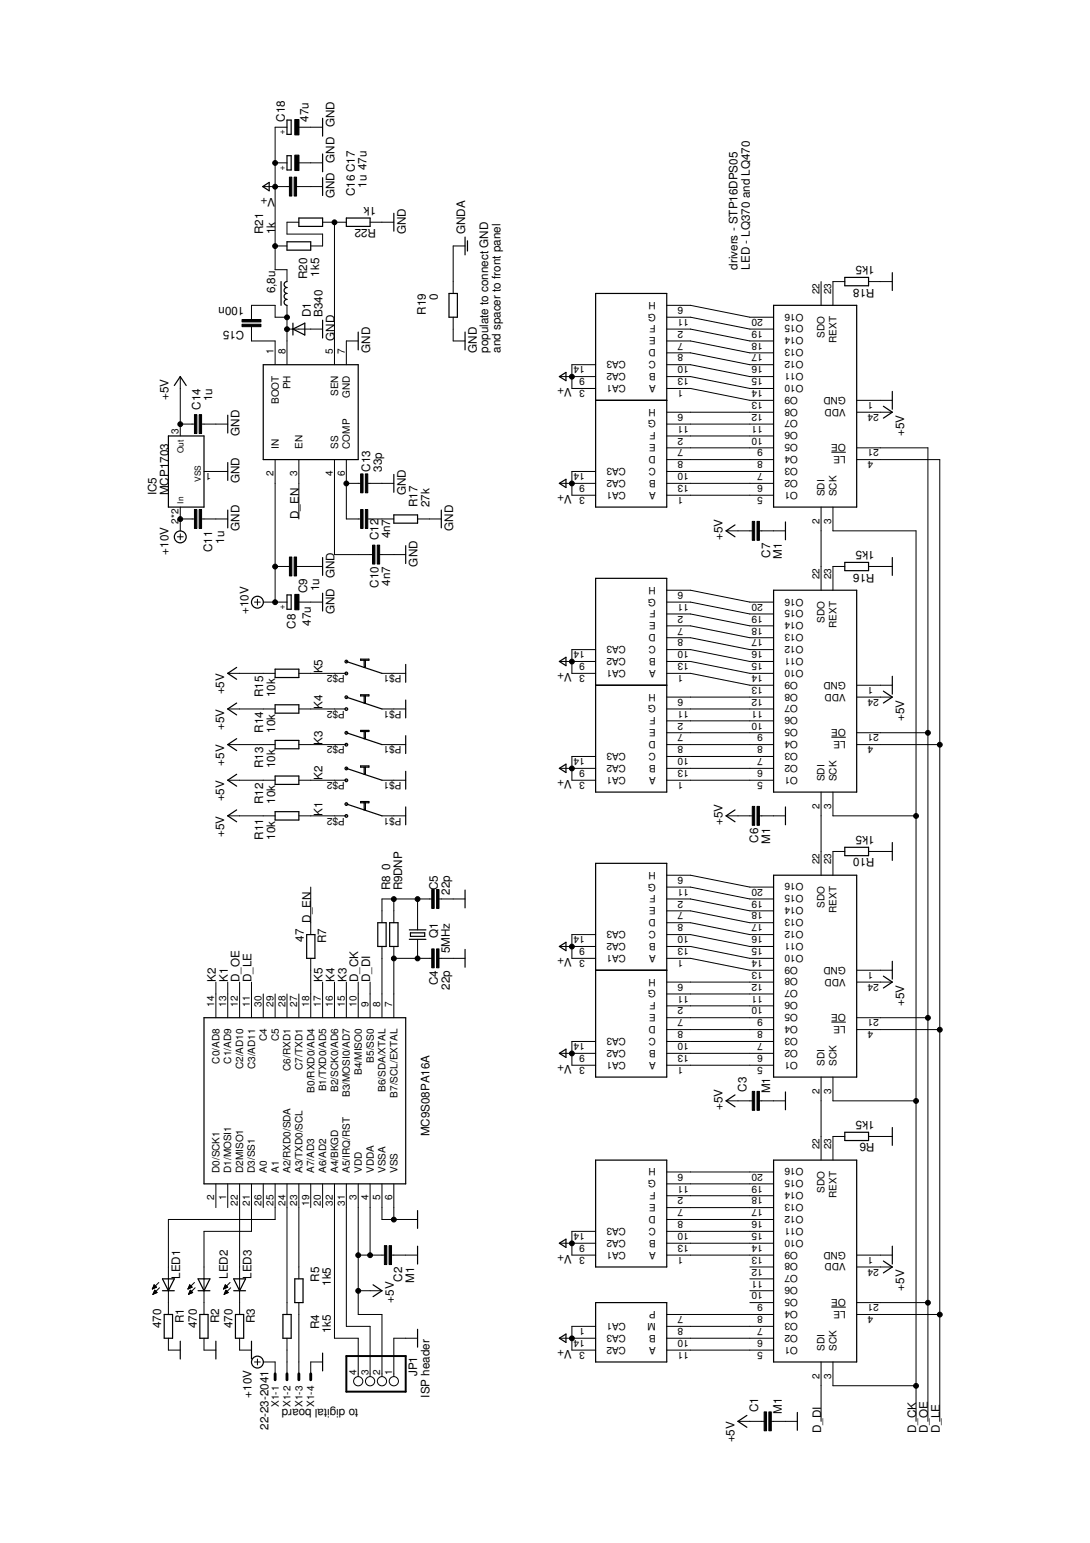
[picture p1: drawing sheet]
<svg xmlns="http://www.w3.org/2000/svg" width="210mm" height="297mm" viewBox="0 0 210 297" stroke-linecap="round" stroke-linejoin="round" font-family="sans-serif">
<defs><g id="words">
<g font-size="2.2">
<text x="54.8" y="23.5" transform="rotate(-90 54.8 23.5)">C18</text>
<text x="59.4" y="23.5" transform="rotate(-90 59.4 23.5)">47u</text>
<text x="64.4" y="24.5" transform="rotate(-90 64.4 24.5)">GND</text>
<text x="64.4" y="31.3" transform="rotate(-90 64.4 31.3)">GND</text>
<text x="53" y="38.2" transform="rotate(-180 53 38.2)">V+</text>
<text x="64.4" y="38.2" transform="rotate(-90 64.4 38.2)">GND</text>
<text x="68.3" y="37.7" transform="rotate(-90 68.3 37.7)">C16 C17</text>
<text x="70.6" y="36.1" transform="rotate(-90 70.6 36.1)">1u 47u</text>
<text x="72.4" y="39.8" transform="rotate(-180 72.4 39.8)">1k</text>
<text x="50.7" y="45.1" transform="rotate(-90 50.7 45.1)">R21</text>
<text x="53" y="45.1" transform="rotate(-90 53 45.1)">1k</text>
<text x="72.4" y="44.1" transform="rotate(-180 72.4 44.1)">R22</text>
<text x="78.1" y="45.1" transform="rotate(-90 78.1 45.1)">GND</text>
<text x="89.6" y="45.1" transform="rotate(-90 89.6 45.1)">GNDA</text>
<text x="59.2" y="53.7" transform="rotate(-90 59.2 53.7)">R20</text>
<text x="61.5" y="53.3" transform="rotate(-90 61.5 53.3)">1k5</text>
<text x="142" y="51.9" transform="rotate(-90 142 51.9)">drivers - STP16DPS05</text>
<text x="144.4" y="51.9" transform="rotate(-90 144.4 51.9)">LED - LQ370 and LQ470</text>
<text x="168.4" y="51.2" transform="rotate(-180 168.4 51.2)">1k5</text>
<text x="47" y="59.1" transform="rotate(-180 47 59.1)">100n</text>
<text x="53" y="56.5" transform="rotate(-90 53 56.5)">6,8u</text>
<text x="84.3" y="57.7" transform="rotate(-90 84.3 57.7)">0</text>
<text x="168.4" y="55.6" transform="rotate(-180 168.4 55.6)">R18</text>
<text x="47" y="63.7" transform="rotate(-180 47 63.7)">C15</text>
<text x="59.8" y="61.1" transform="rotate(-90 59.8 61.1)">D1</text>
<text x="62.1" y="61.1" transform="rotate(-90 62.1 61.1)">B340</text>
<text x="64.4" y="65.6" transform="rotate(-90 64.4 65.6)">GND</text>
<text x="82" y="60.6" transform="rotate(-90 82 60.6)">R19</text>
<text x="71.3" y="67.9" transform="rotate(-90 71.3 67.9)">GND</text>
<text x="91.8" y="67.9" transform="rotate(-90 91.8 67.9)">GND</text>
<text x="94" y="67.9" transform="rotate(-90 94 67.9)">populate to connect GND</text>
<text x="96.4" y="67.9" transform="rotate(-90 96.4 67.9)">and spacer to front panel</text>
<text x="32.4" y="77.1" transform="rotate(-90 32.4 77.1)">+5V</text>
<text x="40.9" y="77.3" transform="rotate(-90 40.9 77.3)">1u</text>
<text x="110.1" y="74.8" transform="rotate(-180 110.1 74.8)">V+</text>
<text x="38.6" y="78.9" transform="rotate(-90 38.6 78.9)">C14</text>
<text x="46.1" y="83.9" transform="rotate(-90 46.1 83.9)">GND</text>
<text x="174.1" y="83.9" transform="rotate(-90 174.1 83.9)">+5V</text>
<text x="30.1" y="95.3" transform="rotate(-90 30.1 95.3)">IC5</text>
<text x="32.4" y="95.3" transform="rotate(-90 32.4 95.3)">MCP1703</text>
<text x="46.1" y="93.1" transform="rotate(-90 46.1 93.1)">GND</text>
<text x="71.3" y="90.8" transform="rotate(-90 71.3 90.8)">C13</text>
<text x="73.6" y="90.8" transform="rotate(-90 73.6 90.8)">33p</text>
<text x="78.1" y="95.3" transform="rotate(-90 78.1 95.3)">GND</text>
<text x="110.1" y="95.3" transform="rotate(-180 110.1 95.3)">V+</text>
<text x="57.6" y="99.9" transform="rotate(-90 57.6 99.9)">D_EN</text>
<text x="80.4" y="97.6" transform="rotate(-90 80.4 97.6)">R17</text>
<text x="82.7" y="97.6" transform="rotate(-90 82.7 97.6)">27k</text>
<text x="32.4" y="106.8" transform="rotate(-90 32.4 106.8)">+10V</text>
<text x="40.9" y="106.3" transform="rotate(-90 40.9 106.3)">C11</text>
<text x="43.2" y="104.7" transform="rotate(-90 43.2 104.7)">1u</text>
<text x="46.1" y="102.2" transform="rotate(-90 46.1 102.2)">GND</text>
<text x="72.9" y="104" transform="rotate(-90 72.9 104)">C12</text>
<text x="75.2" y="103.7" transform="rotate(-90 75.2 103.7)">4n7</text>
<text x="87.3" y="102.2" transform="rotate(-90 87.3 102.2)">GND</text>
<text x="139.2" y="104" transform="rotate(-90 139.2 104)">+5V</text>
<text x="148.3" y="107.3" transform="rotate(-90 148.3 107.3)">C7</text>
<text x="150.6" y="107.6" transform="rotate(-90 150.6 107.6)">M1</text>
<text x="168.4" y="106.1" transform="rotate(-180 168.4 106.1)">1k5</text>
<text x="61.5" y="113.8" transform="rotate(-90 61.5 113.8)">1u</text>
<text x="64.4" y="111.3" transform="rotate(-90 64.4 111.3)">GND</text>
<text x="72.9" y="113.2" transform="rotate(-90 72.9 113.2)">C10</text>
<text x="75.2" y="112.8" transform="rotate(-90 75.2 112.8)">4n7</text>
<text x="80.4" y="109.1" transform="rotate(-90 80.4 109.1)">GND</text>
<text x="168.4" y="110.4" transform="rotate(-180 168.4 110.4)">R16</text>
<text x="47.8" y="118.2" transform="rotate(-90 47.8 118.2)">+10V</text>
<text x="59.2" y="114.2" transform="rotate(-90 59.2 114.2)">C9</text>
<text x="64.4" y="118.2" transform="rotate(-90 64.4 118.2)">GND</text>
<text x="56.9" y="121.1" transform="rotate(-90 56.9 121.1)">C8</text>
<text x="59.8" y="120.5" transform="rotate(-90 59.8 120.5)">47u</text>
<text x="62.1" y="129.6" transform="rotate(-90 62.1 129.6)">K5</text>
<text x="110.1" y="129.6" transform="rotate(-180 110.1 129.6)">V+</text>
<text x="43.2" y="133.7" transform="rotate(-90 43.2 133.7)">+5V</text>
<text x="50.7" y="134.2" transform="rotate(-90 50.7 134.2)">R15</text>
<text x="53" y="134.2" transform="rotate(-90 53 134.2)">10k</text>
<text x="62.1" y="136.5" transform="rotate(-90 62.1 136.5)">K4</text>
<text x="43.2" y="140.5" transform="rotate(-90 43.2 140.5)">+5V</text>
<text x="50.7" y="141.1" transform="rotate(-90 50.7 141.1)">R14</text>
<text x="53" y="141.1" transform="rotate(-90 53 141.1)">10k</text>
<text x="62.1" y="143.3" transform="rotate(-90 62.1 143.3)">K3</text>
<text x="174.1" y="138.8" transform="rotate(-90 174.1 138.8)">+5V</text>
<text x="43.2" y="147.4" transform="rotate(-90 43.2 147.4)">+5V</text>
<text x="50.7" y="147.9" transform="rotate(-90 50.7 147.9)">R13</text>
<text x="53" y="147.9" transform="rotate(-90 53 147.9)">10k</text>
<text x="43.2" y="154.3" transform="rotate(-90 43.2 154.3)">+5V</text>
<text x="50.7" y="154.8" transform="rotate(-90 50.7 154.8)">R12</text>
<text x="53" y="154.8" transform="rotate(-90 53 154.8)">10k</text>
<text x="62.1" y="150.2" transform="rotate(-90 62.1 150.2)">K2</text>
<text x="110.1" y="150.2" transform="rotate(-180 110.1 150.2)">V+</text>
<text x="43.2" y="161.1" transform="rotate(-90 43.2 161.1)">+5V</text>
<text x="50.7" y="161.6" transform="rotate(-90 50.7 161.6)">R11</text>
<text x="53" y="161.6" transform="rotate(-90 53 161.6)">10k</text>
<text x="62.1" y="157.1" transform="rotate(-90 62.1 157.1)">K1</text>
<text x="139.2" y="158.8" transform="rotate(-90 139.2 158.8)">+5V</text>
<text x="168.4" y="160.9" transform="rotate(-180 168.4 160.9)">1k5</text>
<text x="75.2" y="167.4" transform="rotate(-90 75.2 167.4)">0</text>
<text x="146" y="162.2" transform="rotate(-90 146 162.2)">C6</text>
<text x="148.3" y="162.5" transform="rotate(-90 148.3 162.5)">M1</text>
<text x="168.4" y="165.3" transform="rotate(-180 168.4 165.3)">R10</text>
<text x="75.2" y="171.3" transform="rotate(-90 75.2 171.3)">R8</text>
<text x="77.5" y="171.3" transform="rotate(-90 77.5 171.3)">R9DNP</text>
<text x="84.3" y="171.3" transform="rotate(-90 84.3 171.3)">C5</text>
<text x="86.6" y="172.2" transform="rotate(-90 86.6 172.2)">22p</text>
<text x="59.8" y="177.6" transform="rotate(-90 59.8 177.6)">D_EN</text>
<text x="58.5" y="181.3" transform="rotate(-90 58.5 181.3)">47</text>
<text x="62.8" y="181.6" transform="rotate(-90 62.8 181.6)">R7</text>
<text x="84.3" y="180.6" transform="rotate(-90 84.3 180.6)">Q1</text>
<text x="86.6" y="183.5" transform="rotate(-90 86.6 183.5)">5MHz</text>
<text x="110.1" y="184.5" transform="rotate(-180 110.1 184.5)">V+</text>
<text x="41.6" y="189.1" transform="rotate(-90 41.6 189.1)">K2</text>
<text x="43.8" y="189.1" transform="rotate(-90 43.8 189.1)">K1</text>
<text x="46.1" y="189.1" transform="rotate(-90 46.1 189.1)">D_OE</text>
<text x="48.4" y="189.1" transform="rotate(-90 48.4 189.1)">D_LE</text>
<text x="62.1" y="189.1" transform="rotate(-90 62.1 189.1)">K5</text>
<text x="64.4" y="189.1" transform="rotate(-90 64.4 189.1)">K4</text>
<text x="66.7" y="189.1" transform="rotate(-90 66.7 189.1)">K3</text>
<text x="69" y="189.1" transform="rotate(-90 69 189.1)">D_CK</text>
<text x="71.3" y="189.1" transform="rotate(-90 71.3 189.1)">D_DI</text>
<text x="84.3" y="189.6" transform="rotate(-90 84.3 189.6)">C4</text>
<text x="86.6" y="190.5" transform="rotate(-90 86.6 190.5)">22p</text>
<text x="174.1" y="193.6" transform="rotate(-90 174.1 193.6)">+5V</text>
<text x="110.1" y="205.1" transform="rotate(-180 110.1 205.1)">V+</text>
<text x="139.2" y="213.7" transform="rotate(-90 139.2 213.7)">+5V</text>
<text x="143.7" y="210.2" transform="rotate(-90 143.7 210.2)">C3</text>
<text x="148.3" y="210.5" transform="rotate(-90 148.3 210.5)">M1</text>
<text x="168.4" y="215.8" transform="rotate(-180 168.4 215.8)">1k5</text>
<text x="82.7" y="218.8" transform="rotate(-90 82.7 218.8)">MC9S08PA16A</text>
<text x="168.4" y="220.1" transform="rotate(-180 168.4 220.1)">R6</text>
<text x="110.1" y="241.6" transform="rotate(-180 110.1 241.6)">V+</text>
<text x="34.7" y="246.2" transform="rotate(-90 34.7 246.2)">LED1</text>
<text x="43.8" y="246.2" transform="rotate(-90 43.8 246.2)">LED2</text>
<text x="48.4" y="246.2" transform="rotate(-90 48.4 246.2)">LED3</text>
<text x="61.5" y="246.8" transform="rotate(-90 61.5 246.8)">R5</text>
<text x="63.7" y="247.5" transform="rotate(-90 63.7 247.5)">1k5</text>
<text x="75.8" y="250.8" transform="rotate(-90 75.8 250.8)">+5V</text>
<text x="77.5" y="246.8" transform="rotate(-90 77.5 246.8)">C2</text>
<text x="79.7" y="247" transform="rotate(-90 79.7 247)">M1</text>
<text x="174.1" y="248.5" transform="rotate(-90 174.1 248.5)">+5V</text>
<text x="31.1" y="255.7" transform="rotate(-90 31.1 255.7)">470</text>
<text x="35.4" y="254.8" transform="rotate(-90 35.4 254.8)">R1</text>
<text x="37.9" y="255.7" transform="rotate(-90 37.9 255.7)">470</text>
<text x="42.2" y="254.8" transform="rotate(-90 42.2 254.8)">R2</text>
<text x="44.8" y="255.7" transform="rotate(-90 44.8 255.7)">470</text>
<text x="49.1" y="254.8" transform="rotate(-90 49.1 254.8)">R3</text>
<text x="61.5" y="255.9" transform="rotate(-90 61.5 255.9)">R4</text>
<text x="63.7" y="256.7" transform="rotate(-90 63.7 256.7)">1k5</text>
<text x="110.1" y="259.9" transform="rotate(-180 110.1 259.9)">V+</text>
<text x="48.4" y="269.1" transform="rotate(-90 48.4 269.1)">+10V</text>
<text x="80.3" y="264.9" transform="rotate(-90 80.3 264.9)">JP1</text>
<text x="82.7" y="269.1" transform="rotate(-90 82.7 269.1)">ISP header</text>
<text x="51.7" y="275.3" transform="rotate(-90 51.7 275.3)">22-23-2041</text>
<text x="69" y="271.3" transform="rotate(-180 69 271.3)">to digital board</text>
<text x="146" y="271.9" transform="rotate(-90 146 271.9)">C1</text>
<text x="150.6" y="272.2" transform="rotate(-90 150.6 272.2)">M1</text>
<text x="158.1" y="275.9" transform="rotate(-90 158.1 275.9)">D_DI</text>
<text x="176.4" y="275.9" transform="rotate(-90 176.4 275.9)">D_CK</text>
<text x="178.7" y="275.9" transform="rotate(-90 178.7 275.9)">D_OE</text>
<text x="181" y="275.9" transform="rotate(-90 181 275.9)">D_LE</text>
<text x="141.4" y="277.7" transform="rotate(-90 141.4 277.7)">+5V</text>
</g>
<g font-size="1.9">
<text x="126.3" y="58.1" transform="rotate(-180 126.3 58.1)">H</text>
<text x="131.6" y="59.1" transform="rotate(-180 131.6 59.1)">6</text>
<text x="157.8" y="56.7" transform="rotate(-90 157.8 56.7)">22</text>
<text x="160.1" y="56.7" transform="rotate(-90 160.1 56.7)">23</text>
<text x="126.3" y="64.9" transform="rotate(-180 126.3 64.9)">E</text>
<text x="126.3" y="62.7" transform="rotate(-180 126.3 62.7)">F</text>
<text x="126.3" y="60.4" transform="rotate(-180 126.3 60.4)">G</text>
<text x="131.6" y="66" transform="rotate(-180 131.6 66)">7</text>
<text x="131.6" y="63.7" transform="rotate(-180 131.6 63.7)">2</text>
<text x="132.6" y="61.4" transform="rotate(-180 132.6 61.4)">11</text>
<text x="146.9" y="66" transform="rotate(-180 146.9 66)">18</text>
<text x="146.9" y="63.7" transform="rotate(-180 146.9 63.7)">19</text>
<text x="146.9" y="61.4" transform="rotate(-180 146.9 61.4)">20</text>
<text x="154.7" y="64.9" transform="rotate(-180 154.7 64.9)">O14</text>
<text x="154.7" y="62.7" transform="rotate(-180 154.7 62.7)">O15</text>
<text x="154.7" y="60.4" transform="rotate(-180 154.7 60.4)">O16</text>
<text x="158.8" y="65" transform="rotate(-90 158.8 65)">SDO</text>
<text x="52.7" y="68.1" transform="rotate(-90 52.7 68.1)">1</text>
<text x="55" y="68.1" transform="rotate(-90 55 68.1)">8</text>
<text x="64.1" y="68.1" transform="rotate(-90 64.1 68.1)">5</text>
<text x="66.4" y="68.1" transform="rotate(-90 66.4 68.1)">7</text>
<text x="112.6" y="70.5" transform="rotate(-180 112.6 70.5)">14</text>
<text x="120.5" y="71.8" transform="rotate(-180 120.5 71.8)">CA2</text>
<text x="120.5" y="69.5" transform="rotate(-180 120.5 69.5)">CA3</text>
<text x="126.3" y="71.8" transform="rotate(-180 126.3 71.8)">B</text>
<text x="126.3" y="69.5" transform="rotate(-180 126.3 69.5)">C</text>
<text x="126.3" y="67.2" transform="rotate(-180 126.3 67.2)">D</text>
<text x="131.6" y="68.2" transform="rotate(-180 131.6 68.2)">8</text>
<text x="132.6" y="70.5" transform="rotate(-180 132.6 70.5)">10</text>
<text x="146.9" y="70.5" transform="rotate(-180 146.9 70.5)">16</text>
<text x="146.9" y="68.2" transform="rotate(-180 146.9 68.2)">17</text>
<text x="154.7" y="71.8" transform="rotate(-180 154.7 71.8)">O11</text>
<text x="154.7" y="69.5" transform="rotate(-180 154.7 69.5)">O12</text>
<text x="154.7" y="67.2" transform="rotate(-180 154.7 67.2)">O13</text>
<text x="161.1" y="66" transform="rotate(-90 161.1 66)">REXT</text>
<text x="53.7" y="77.8" transform="rotate(-90 53.7 77.8)">BOOT</text>
<text x="56" y="75" transform="rotate(-90 56 75)">PH</text>
<text x="65.1" y="76.3" transform="rotate(-90 65.1 76.3)">SEN</text>
<text x="67.4" y="76.6" transform="rotate(-90 67.4 76.6)">GND</text>
<text x="112.6" y="75.1" transform="rotate(-180 112.6 75.1)">3</text>
<text x="112.6" y="72.8" transform="rotate(-180 112.6 72.8)">9</text>
<text x="120.5" y="74.1" transform="rotate(-180 120.5 74.1)">CA1</text>
<text x="126.3" y="74.1" transform="rotate(-180 126.3 74.1)">A</text>
<text x="131.6" y="75.1" transform="rotate(-180 131.6 75.1)">1</text>
<text x="132.6" y="72.8" transform="rotate(-180 132.6 72.8)">13</text>
<text x="146.9" y="77.4" transform="rotate(-180 146.9 77.4)">13</text>
<text x="146.9" y="75.1" transform="rotate(-180 146.9 75.1)">14</text>
<text x="146.9" y="72.8" transform="rotate(-180 146.9 72.8)">15</text>
<text x="153.6" y="76.4" transform="rotate(-180 153.6 76.4)">O9</text>
<text x="154.7" y="74.1" transform="rotate(-180 154.7 74.1)">O10</text>
<text x="162.9" y="76.4" transform="rotate(-180 162.9 76.4)">GND</text>
<text x="168.2" y="77.4" transform="rotate(-180 168.2 77.4)">1</text>
<text x="34.4" y="83.6" transform="rotate(-90 34.4 83.6)">3</text>
<text x="126.3" y="83.2" transform="rotate(-180 126.3 83.2)">F</text>
<text x="126.3" y="80.9" transform="rotate(-180 126.3 80.9)">G</text>
<text x="126.3" y="78.7" transform="rotate(-180 126.3 78.7)">H</text>
<text x="131.6" y="79.7" transform="rotate(-180 131.6 79.7)">6</text>
<text x="132.6" y="82" transform="rotate(-180 132.6 82)">11</text>
<text x="146.9" y="82" transform="rotate(-180 146.9 82)">11</text>
<text x="146.9" y="79.7" transform="rotate(-180 146.9 79.7)">12</text>
<text x="153.6" y="83.2" transform="rotate(-180 153.6 83.2)">O6</text>
<text x="153.6" y="80.9" transform="rotate(-180 153.6 80.9)">O7</text>
<text x="153.6" y="78.7" transform="rotate(-180 153.6 78.7)">O8</text>
<text x="162.9" y="78.7" transform="rotate(-180 162.9 78.7)">VDD</text>
<text x="169.2" y="79.7" transform="rotate(-180 169.2 79.7)">24</text>
<text x="53.7" y="86.4" transform="rotate(-90 53.7 86.4)">IN</text>
<text x="58.2" y="86.4" transform="rotate(-90 58.2 86.4)">EN</text>
<text x="65.1" y="86.4" transform="rotate(-90 65.1 86.4)">SS</text>
<text x="67.4" y="86.4" transform="rotate(-90 67.4 86.4)">COMP</text>
<text x="126.3" y="87.8" transform="rotate(-180 126.3 87.8)">D</text>
<text x="126.3" y="85.5" transform="rotate(-180 126.3 85.5)">E</text>
<text x="131.6" y="88.8" transform="rotate(-180 131.6 88.8)">8</text>
<text x="131.6" y="86.5" transform="rotate(-180 131.6 86.5)">7</text>
<text x="131.6" y="84.2" transform="rotate(-180 131.6 84.2)">2</text>
<text x="146.9" y="88.8" transform="rotate(-180 146.9 88.8)">8</text>
<text x="146.9" y="86.5" transform="rotate(-180 146.9 86.5)">9</text>
<text x="146.9" y="84.2" transform="rotate(-180 146.9 84.2)">10</text>
<text x="153.6" y="87.8" transform="rotate(-180 153.6 87.8)">O4</text>
<text x="153.6" y="85.5" transform="rotate(-180 153.6 85.5)">O5</text>
<text x="162.9" y="87.8" transform="rotate(-180 162.9 87.8)">LE</text>
<text x="162.9" y="85.5" transform="rotate(-180 162.9 85.5)">OE</text>
<text x="168.2" y="88.8" transform="rotate(-180 168.2 88.8)">4</text>
<text x="169.2" y="86.5" transform="rotate(-180 169.2 86.5)">21</text>
<text x="40.7" y="91.1" transform="rotate(-180 40.7 91.1)">1</text>
<text x="52.7" y="91.7" transform="rotate(-90 52.7 91.7)">2</text>
<text x="57.2" y="91.7" transform="rotate(-90 57.2 91.7)">3</text>
<text x="64.1" y="91.7" transform="rotate(-90 64.1 91.7)">4</text>
<text x="66.4" y="91.7" transform="rotate(-90 66.4 91.7)">6</text>
<text x="112.6" y="95.7" transform="rotate(-180 112.6 95.7)">3</text>
<text x="112.6" y="93.4" transform="rotate(-180 112.6 93.4)">9</text>
<text x="112.6" y="91.1" transform="rotate(-180 112.6 91.1)">14</text>
<text x="120.5" y="94.7" transform="rotate(-180 120.5 94.7)">CA1</text>
<text x="120.5" y="92.4" transform="rotate(-180 120.5 92.4)">CA2</text>
<text x="120.5" y="90.1" transform="rotate(-180 120.5 90.1)">CA3</text>
<text x="126.3" y="94.7" transform="rotate(-180 126.3 94.7)">A</text>
<text x="126.3" y="92.4" transform="rotate(-180 126.3 92.4)">B</text>
<text x="126.3" y="90.1" transform="rotate(-180 126.3 90.1)">C</text>
<text x="131.6" y="95.7" transform="rotate(-180 131.6 95.7)">1</text>
<text x="132.6" y="93.4" transform="rotate(-180 132.6 93.4)">13</text>
<text x="132.6" y="91.1" transform="rotate(-180 132.6 91.1)">10</text>
<text x="146.9" y="95.7" transform="rotate(-180 146.9 95.7)">5</text>
<text x="146.9" y="93.4" transform="rotate(-180 146.9 93.4)">6</text>
<text x="146.9" y="91.1" transform="rotate(-180 146.9 91.1)">7</text>
<text x="153.6" y="94.7" transform="rotate(-180 153.6 94.7)">O1</text>
<text x="153.6" y="92.4" transform="rotate(-180 153.6 92.4)">O2</text>
<text x="153.6" y="90.1" transform="rotate(-180 153.6 90.1)">O3</text>
<text x="158.8" y="95.5" transform="rotate(-90 158.8 95.5)">SDI</text>
<text x="161.1" y="95.5" transform="rotate(-90 161.1 95.5)">SCK</text>
<text x="34.4" y="100.8" transform="rotate(-90 34.4 100.8)">2*2</text>
<text x="157.8" y="100.8" transform="rotate(-90 157.8 100.8)">2</text>
<text x="160.1" y="100.8" transform="rotate(-90 160.1 100.8)">3</text>
<text x="126.3" y="112.9" transform="rotate(-180 126.3 112.9)">H</text>
<text x="131.6" y="113.9" transform="rotate(-180 131.6 113.9)">6</text>
<text x="157.8" y="111.5" transform="rotate(-90 157.8 111.5)">22</text>
<text x="160.1" y="111.5" transform="rotate(-90 160.1 111.5)">23</text>
<text x="126.3" y="119.8" transform="rotate(-180 126.3 119.8)">E</text>
<text x="126.3" y="117.5" transform="rotate(-180 126.3 117.5)">F</text>
<text x="126.3" y="115.2" transform="rotate(-180 126.3 115.2)">G</text>
<text x="131.6" y="118.5" transform="rotate(-180 131.6 118.5)">2</text>
<text x="132.6" y="116.2" transform="rotate(-180 132.6 116.2)">11</text>
<text x="146.9" y="118.5" transform="rotate(-180 146.9 118.5)">19</text>
<text x="146.9" y="116.2" transform="rotate(-180 146.9 116.2)">20</text>
<text x="154.7" y="119.8" transform="rotate(-180 154.7 119.8)">O14</text>
<text x="154.7" y="117.5" transform="rotate(-180 154.7 117.5)">O15</text>
<text x="154.7" y="115.2" transform="rotate(-180 154.7 115.2)">O16</text>
<text x="158.8" y="119.9" transform="rotate(-90 158.8 119.9)">SDO</text>
<text x="112.6" y="125.4" transform="rotate(-180 112.6 125.4)">14</text>
<text x="120.5" y="124.4" transform="rotate(-180 120.5 124.4)">CA3</text>
<text x="126.3" y="124.4" transform="rotate(-180 126.3 124.4)">C</text>
<text x="126.3" y="122.1" transform="rotate(-180 126.3 122.1)">D</text>
<text x="131.6" y="123.1" transform="rotate(-180 131.6 123.1)">8</text>
<text x="131.6" y="120.8" transform="rotate(-180 131.6 120.8)">7</text>
<text x="132.6" y="125.4" transform="rotate(-180 132.6 125.4)">10</text>
<text x="146.9" y="125.4" transform="rotate(-180 146.9 125.4)">16</text>
<text x="146.9" y="123.1" transform="rotate(-180 146.9 123.1)">17</text>
<text x="146.9" y="120.8" transform="rotate(-180 146.9 120.8)">18</text>
<text x="154.7" y="124.4" transform="rotate(-180 154.7 124.4)">O12</text>
<text x="154.7" y="122.1" transform="rotate(-180 154.7 122.1)">O13</text>
<text x="161.1" y="120.9" transform="rotate(-90 161.1 120.9)">REXT</text>
<text x="66.4" y="129.9" transform="rotate(-180 66.4 129.9)">P$2</text>
<text x="77.3" y="129.9" transform="rotate(-180 77.3 129.9)">P$1</text>
<text x="112.6" y="129.9" transform="rotate(-180 112.6 129.9)">3</text>
<text x="112.6" y="127.7" transform="rotate(-180 112.6 127.7)">9</text>
<text x="120.5" y="128.9" transform="rotate(-180 120.5 128.9)">CA1</text>
<text x="120.5" y="126.7" transform="rotate(-180 120.5 126.7)">CA2</text>
<text x="126.3" y="128.9" transform="rotate(-180 126.3 128.9)">A</text>
<text x="126.3" y="126.7" transform="rotate(-180 126.3 126.7)">B</text>
<text x="131.6" y="129.9" transform="rotate(-180 131.6 129.9)">1</text>
<text x="132.6" y="127.7" transform="rotate(-180 132.6 127.7)">13</text>
<text x="146.9" y="129.9" transform="rotate(-180 146.9 129.9)">14</text>
<text x="146.9" y="127.7" transform="rotate(-180 146.9 127.7)">15</text>
<text x="153.6" y="131.2" transform="rotate(-180 153.6 131.2)">O9</text>
<text x="154.7" y="128.9" transform="rotate(-180 154.7 128.9)">O10</text>
<text x="154.7" y="126.7" transform="rotate(-180 154.7 126.7)">O11</text>
<text x="162.9" y="131.2" transform="rotate(-180 162.9 131.2)">GND</text>
<text x="66.4" y="136.8" transform="rotate(-180 66.4 136.8)">P$2</text>
<text x="77.3" y="136.8" transform="rotate(-180 77.3 136.8)">P$1</text>
<text x="126.3" y="135.8" transform="rotate(-180 126.3 135.8)">G</text>
<text x="126.3" y="133.5" transform="rotate(-180 126.3 133.5)">H</text>
<text x="131.6" y="134.5" transform="rotate(-180 131.6 134.5)">6</text>
<text x="132.6" y="136.8" transform="rotate(-180 132.6 136.8)">11</text>
<text x="146.9" y="136.8" transform="rotate(-180 146.9 136.8)">11</text>
<text x="146.9" y="134.5" transform="rotate(-180 146.9 134.5)">12</text>
<text x="146.9" y="132.2" transform="rotate(-180 146.9 132.2)">13</text>
<text x="153.6" y="135.8" transform="rotate(-180 153.6 135.8)">O7</text>
<text x="153.6" y="133.5" transform="rotate(-180 153.6 133.5)">O8</text>
<text x="162.9" y="133.5" transform="rotate(-180 162.9 133.5)">VDD</text>
<text x="168.2" y="132.2" transform="rotate(-180 168.2 132.2)">1</text>
<text x="169.2" y="134.5" transform="rotate(-180 169.2 134.5)">24</text>
<text x="66.4" y="143.7" transform="rotate(-180 66.4 143.7)">P$2</text>
<text x="77.3" y="143.7" transform="rotate(-180 77.3 143.7)">P$1</text>
<text x="126.3" y="142.7" transform="rotate(-180 126.3 142.7)">D</text>
<text x="126.3" y="140.4" transform="rotate(-180 126.3 140.4)">E</text>
<text x="126.3" y="138.1" transform="rotate(-180 126.3 138.1)">F</text>
<text x="131.6" y="143.7" transform="rotate(-180 131.6 143.7)">8</text>
<text x="131.6" y="141.4" transform="rotate(-180 131.6 141.4)">7</text>
<text x="131.6" y="139.1" transform="rotate(-180 131.6 139.1)">2</text>
<text x="146.9" y="143.7" transform="rotate(-180 146.9 143.7)">8</text>
<text x="146.9" y="141.4" transform="rotate(-180 146.9 141.4)">9</text>
<text x="146.9" y="139.1" transform="rotate(-180 146.9 139.1)">10</text>
<text x="153.6" y="142.7" transform="rotate(-180 153.6 142.7)">O4</text>
<text x="153.6" y="140.4" transform="rotate(-180 153.6 140.4)">O5</text>
<text x="153.6" y="138.1" transform="rotate(-180 153.6 138.1)">O6</text>
<text x="162.9" y="142.7" transform="rotate(-180 162.9 142.7)">LE</text>
<text x="162.9" y="140.4" transform="rotate(-180 162.9 140.4)">OE</text>
<text x="168.2" y="143.7" transform="rotate(-180 168.2 143.7)">4</text>
<text x="169.2" y="141.4" transform="rotate(-180 169.2 141.4)">21</text>
<text x="112.6" y="148.2" transform="rotate(-180 112.6 148.2)">9</text>
<text x="112.6" y="145.9" transform="rotate(-180 112.6 145.9)">14</text>
<text x="120.5" y="149.5" transform="rotate(-180 120.5 149.5)">CA1</text>
<text x="120.5" y="147.2" transform="rotate(-180 120.5 147.2)">CA2</text>
<text x="120.5" y="144.9" transform="rotate(-180 120.5 144.9)">CA3</text>
<text x="126.3" y="149.5" transform="rotate(-180 126.3 149.5)">A</text>
<text x="126.3" y="147.2" transform="rotate(-180 126.3 147.2)">B</text>
<text x="126.3" y="144.9" transform="rotate(-180 126.3 144.9)">C</text>
<text x="132.6" y="148.2" transform="rotate(-180 132.6 148.2)">13</text>
<text x="132.6" y="145.9" transform="rotate(-180 132.6 145.9)">10</text>
<text x="146.9" y="148.2" transform="rotate(-180 146.9 148.2)">6</text>
<text x="146.9" y="145.9" transform="rotate(-180 146.9 145.9)">7</text>
<text x="153.6" y="149.5" transform="rotate(-180 153.6 149.5)">O1</text>
<text x="153.6" y="147.2" transform="rotate(-180 153.6 147.2)">O2</text>
<text x="153.6" y="144.9" transform="rotate(-180 153.6 144.9)">O3</text>
<text x="66.4" y="150.5" transform="rotate(-180 66.4 150.5)">P$2</text>
<text x="77.3" y="150.5" transform="rotate(-180 77.3 150.5)">P$1</text>
<text x="112.6" y="150.5" transform="rotate(-180 112.6 150.5)">3</text>
<text x="131.6" y="150.5" transform="rotate(-180 131.6 150.5)">1</text>
<text x="146.9" y="150.5" transform="rotate(-180 146.9 150.5)">5</text>
<text x="157.8" y="155.7" transform="rotate(-90 157.8 155.7)">2</text>
<text x="158.8" y="150.4" transform="rotate(-90 158.8 150.4)">SDI</text>
<text x="160.1" y="155.7" transform="rotate(-90 160.1 155.7)">3</text>
<text x="161.1" y="150.4" transform="rotate(-90 161.1 150.4)">SCK</text>
<text x="66.4" y="157.4" transform="rotate(-180 66.4 157.4)">P$2</text>
<text x="77.3" y="157.4" transform="rotate(-180 77.3 157.4)">P$1</text>
<text x="126.3" y="167.8" transform="rotate(-180 126.3 167.8)">H</text>
<text x="157.8" y="166.4" transform="rotate(-90 157.8 166.4)">22</text>
<text x="160.1" y="166.4" transform="rotate(-90 160.1 166.4)">23</text>
<text x="126.3" y="172.4" transform="rotate(-180 126.3 172.4)">F</text>
<text x="126.3" y="170.1" transform="rotate(-180 126.3 170.1)">G</text>
<text x="131.6" y="173.4" transform="rotate(-180 131.6 173.4)">2</text>
<text x="131.6" y="168.8" transform="rotate(-180 131.6 168.8)">6</text>
<text x="132.6" y="171.1" transform="rotate(-180 132.6 171.1)">11</text>
<text x="146.9" y="173.4" transform="rotate(-180 146.9 173.4)">19</text>
<text x="146.9" y="171.1" transform="rotate(-180 146.9 171.1)">20</text>
<text x="154.7" y="172.4" transform="rotate(-180 154.7 172.4)">O15</text>
<text x="154.7" y="170.1" transform="rotate(-180 154.7 170.1)">O16</text>
<text x="120.5" y="179.2" transform="rotate(-180 120.5 179.2)">CA3</text>
<text x="126.3" y="179.2" transform="rotate(-180 126.3 179.2)">C</text>
<text x="126.3" y="176.9" transform="rotate(-180 126.3 176.9)">D</text>
<text x="126.3" y="174.7" transform="rotate(-180 126.3 174.7)">E</text>
<text x="131.6" y="177.9" transform="rotate(-180 131.6 177.9)">8</text>
<text x="131.6" y="175.7" transform="rotate(-180 131.6 175.7)">7</text>
<text x="146.9" y="177.9" transform="rotate(-180 146.9 177.9)">17</text>
<text x="146.9" y="175.7" transform="rotate(-180 146.9 175.7)">18</text>
<text x="154.7" y="179.2" transform="rotate(-180 154.7 179.2)">O12</text>
<text x="154.7" y="176.9" transform="rotate(-180 154.7 176.9)">O13</text>
<text x="154.7" y="174.7" transform="rotate(-180 154.7 174.7)">O14</text>
<text x="158.8" y="174.8" transform="rotate(-90 158.8 174.8)">SDO</text>
<text x="161.1" y="175.7" transform="rotate(-90 161.1 175.7)">REXT</text>
<text x="112.6" y="184.8" transform="rotate(-180 112.6 184.8)">3</text>
<text x="112.6" y="182.5" transform="rotate(-180 112.6 182.5)">9</text>
<text x="112.6" y="180.2" transform="rotate(-180 112.6 180.2)">14</text>
<text x="120.5" y="183.8" transform="rotate(-180 120.5 183.8)">CA1</text>
<text x="120.5" y="181.5" transform="rotate(-180 120.5 181.5)">CA2</text>
<text x="126.3" y="183.8" transform="rotate(-180 126.3 183.8)">A</text>
<text x="126.3" y="181.5" transform="rotate(-180 126.3 181.5)">B</text>
<text x="131.6" y="184.8" transform="rotate(-180 131.6 184.8)">1</text>
<text x="132.6" y="182.5" transform="rotate(-180 132.6 182.5)">13</text>
<text x="132.6" y="180.2" transform="rotate(-180 132.6 180.2)">10</text>
<text x="146.9" y="184.8" transform="rotate(-180 146.9 184.8)">14</text>
<text x="146.9" y="182.5" transform="rotate(-180 146.9 182.5)">15</text>
<text x="146.9" y="180.2" transform="rotate(-180 146.9 180.2)">16</text>
<text x="154.7" y="183.8" transform="rotate(-180 154.7 183.8)">O10</text>
<text x="154.7" y="181.5" transform="rotate(-180 154.7 181.5)">O11</text>
<text x="126.3" y="190.7" transform="rotate(-180 126.3 190.7)">G</text>
<text x="126.3" y="188.4" transform="rotate(-180 126.3 188.4)">H</text>
<text x="131.6" y="189.4" transform="rotate(-180 131.6 189.4)">6</text>
<text x="132.6" y="191.7" transform="rotate(-180 132.6 191.7)">11</text>
<text x="146.9" y="191.7" transform="rotate(-180 146.9 191.7)">11</text>
<text x="146.9" y="189.4" transform="rotate(-180 146.9 189.4)">12</text>
<text x="146.9" y="187.1" transform="rotate(-180 146.9 187.1)">13</text>
<text x="153.6" y="190.7" transform="rotate(-180 153.6 190.7)">O7</text>
<text x="153.6" y="188.4" transform="rotate(-180 153.6 188.4)">O8</text>
<text x="153.6" y="186.1" transform="rotate(-180 153.6 186.1)">O9</text>
<text x="162.9" y="188.4" transform="rotate(-180 162.9 188.4)">VDD</text>
<text x="162.9" y="186.1" transform="rotate(-180 162.9 186.1)">GND</text>
<text x="168.2" y="187.1" transform="rotate(-180 168.2 187.1)">1</text>
<text x="169.2" y="189.4" transform="rotate(-180 169.2 189.4)">24</text>
<text x="41.2" y="193.8" transform="rotate(-90 41.2 193.8)">14</text>
<text x="43.5" y="193.8" transform="rotate(-90 43.5 193.8)">13</text>
<text x="45.8" y="193.8" transform="rotate(-90 45.8 193.8)">12</text>
<text x="48.1" y="193.8" transform="rotate(-90 48.1 193.8)">11</text>
<text x="50.4" y="193.8" transform="rotate(-90 50.4 193.8)">30</text>
<text x="52.7" y="193.8" transform="rotate(-90 52.7 193.8)">29</text>
<text x="55" y="193.8" transform="rotate(-90 55 193.8)">28</text>
<text x="57.2" y="193.8" transform="rotate(-90 57.2 193.8)">27</text>
<text x="59.5" y="193.8" transform="rotate(-90 59.5 193.8)">18</text>
<text x="61.8" y="193.8" transform="rotate(-90 61.8 193.8)">17</text>
<text x="64.1" y="193.8" transform="rotate(-90 64.1 193.8)">16</text>
<text x="66.4" y="193.8" transform="rotate(-90 66.4 193.8)">15</text>
<text x="68.7" y="193.8" transform="rotate(-90 68.7 193.8)">10</text>
<text x="71" y="193.8" transform="rotate(-90 71 193.8)">9</text>
<text x="73.2" y="193.8" transform="rotate(-90 73.2 193.8)">8</text>
<text x="75.5" y="193.8" transform="rotate(-90 75.5 193.8)">7</text>
<text x="126.3" y="197.5" transform="rotate(-180 126.3 197.5)">D</text>
<text x="126.3" y="195.2" transform="rotate(-180 126.3 195.2)">E</text>
<text x="126.3" y="192.9" transform="rotate(-180 126.3 192.9)">F</text>
<text x="131.6" y="196.2" transform="rotate(-180 131.6 196.2)">7</text>
<text x="131.6" y="193.9" transform="rotate(-180 131.6 193.9)">2</text>
<text x="146.9" y="196.2" transform="rotate(-180 146.9 196.2)">9</text>
<text x="146.9" y="193.9" transform="rotate(-180 146.9 193.9)">10</text>
<text x="153.6" y="197.5" transform="rotate(-180 153.6 197.5)">O4</text>
<text x="153.6" y="195.2" transform="rotate(-180 153.6 195.2)">O5</text>
<text x="153.6" y="192.9" transform="rotate(-180 153.6 192.9)">O6</text>
<text x="162.9" y="197.5" transform="rotate(-180 162.9 197.5)">LE</text>
<text x="162.9" y="195.2" transform="rotate(-180 162.9 195.2)">OE</text>
<text x="169.2" y="196.2" transform="rotate(-180 169.2 196.2)">21</text>
<text x="51.4" y="200.5" transform="rotate(-90 51.4 200.5)">C4</text>
<text x="53.7" y="200.5" transform="rotate(-90 53.7 200.5)">C5</text>
<text x="112.6" y="203.1" transform="rotate(-180 112.6 203.1)">9</text>
<text x="112.6" y="200.8" transform="rotate(-180 112.6 200.8)">14</text>
<text x="120.5" y="202.1" transform="rotate(-180 120.5 202.1)">CA2</text>
<text x="120.5" y="199.8" transform="rotate(-180 120.5 199.8)">CA3</text>
<text x="126.3" y="202.1" transform="rotate(-180 126.3 202.1)">B</text>
<text x="126.3" y="199.8" transform="rotate(-180 126.3 199.8)">C</text>
<text x="131.6" y="198.5" transform="rotate(-180 131.6 198.5)">8</text>
<text x="132.6" y="203.1" transform="rotate(-180 132.6 203.1)">13</text>
<text x="132.6" y="200.8" transform="rotate(-180 132.6 200.8)">10</text>
<text x="146.9" y="203.1" transform="rotate(-180 146.9 203.1)">6</text>
<text x="146.9" y="200.8" transform="rotate(-180 146.9 200.8)">7</text>
<text x="146.9" y="198.5" transform="rotate(-180 146.9 198.5)">8</text>
<text x="153.6" y="202.1" transform="rotate(-180 153.6 202.1)">O2</text>
<text x="153.6" y="199.8" transform="rotate(-180 153.6 199.8)">O3</text>
<text x="168.2" y="198.5" transform="rotate(-180 168.2 198.5)">4</text>
<text x="42.3" y="204.8" transform="rotate(-90 42.3 204.8)">C0/AD8</text>
<text x="44.5" y="204.8" transform="rotate(-90 44.5 204.8)">C1/AD9</text>
<text x="46.8" y="205.8" transform="rotate(-90 46.8 205.8)">C2/AD10</text>
<text x="49.1" y="205.8" transform="rotate(-90 49.1 205.8)">C3/AD11</text>
<text x="56" y="206.1" transform="rotate(-90 56 206.1)">C6/RXD1</text>
<text x="58.3" y="205.9" transform="rotate(-90 58.3 205.9)">C7/TXD1</text>
<text x="69.7" y="206.9" transform="rotate(-90 69.7 206.9)">B4/MISO0</text>
<text x="72" y="204.6" transform="rotate(-90 72 204.6)">B5/SS0</text>
<text x="112.6" y="205.4" transform="rotate(-180 112.6 205.4)">3</text>
<text x="120.5" y="204.4" transform="rotate(-180 120.5 204.4)">CA1</text>
<text x="126.3" y="204.4" transform="rotate(-180 126.3 204.4)">A</text>
<text x="131.6" y="205.4" transform="rotate(-180 131.6 205.4)">1</text>
<text x="146.9" y="205.4" transform="rotate(-180 146.9 205.4)">5</text>
<text x="153.6" y="204.4" transform="rotate(-180 153.6 204.4)">O1</text>
<text x="158.8" y="205.2" transform="rotate(-90 158.8 205.2)">SDI</text>
<text x="161.1" y="205.2" transform="rotate(-90 161.1 205.2)">SCK</text>
<text x="60.5" y="210.3" transform="rotate(-90 60.5 210.3)">B0/RXD0/AD4</text>
<text x="62.8" y="210.1" transform="rotate(-90 62.8 210.1)">B1/TXD0/AD5</text>
<text x="65.1" y="210.2" transform="rotate(-90 65.1 210.2)">B2/SCK0/AD6</text>
<text x="67.4" y="211.2" transform="rotate(-90 67.4 211.2)">B3/MOSI0/AD7</text>
<text x="74.2" y="210.2" transform="rotate(-90 74.2 210.2)">B6/SDA/XTAL</text>
<text x="76.5" y="211.3" transform="rotate(-90 76.5 211.3)">B7/SCL/EXTAL</text>
<text x="157.8" y="210.5" transform="rotate(-90 157.8 210.5)">2</text>
<text x="160.1" y="210.5" transform="rotate(-90 160.1 210.5)">3</text>
<text x="157.8" y="221.2" transform="rotate(-90 157.8 221.2)">22</text>
<text x="160.1" y="221.2" transform="rotate(-90 160.1 221.2)">23</text>
<text x="42.2" y="225.8" transform="rotate(-90 42.2 225.8)">D0/SCK1</text>
<text x="44.5" y="225.8" transform="rotate(-90 44.5 225.8)">D1/MOSI1</text>
<text x="46.8" y="225.8" transform="rotate(-90 46.8 225.8)">D2MISO1</text>
<text x="49.1" y="225.8" transform="rotate(-90 49.1 225.8)">D3/SS1</text>
<text x="51.4" y="225.8" transform="rotate(-90 51.4 225.8)">A0</text>
<text x="53.7" y="225.8" transform="rotate(-90 53.7 225.8)">A1</text>
<text x="56" y="225.8" transform="rotate(-90 56 225.8)">A2/RXD0/SDA</text>
<text x="58.2" y="225.8" transform="rotate(-90 58.2 225.8)">A3/TXD0/SCL</text>
<text x="60.5" y="225.8" transform="rotate(-90 60.5 225.8)">A7/AD3</text>
<text x="62.8" y="225.8" transform="rotate(-90 62.8 225.8)">A6/AD2</text>
<text x="65.1" y="225.8" transform="rotate(-90 65.1 225.8)">A4/BKGD</text>
<text x="67.4" y="225.8" transform="rotate(-90 67.4 225.8)">A5/IRQ/RST</text>
<text x="69.7" y="225.8" transform="rotate(-90 69.7 225.8)">VDD</text>
<text x="72" y="225.8" transform="rotate(-90 72 225.8)">VDDA</text>
<text x="74.2" y="225.8" transform="rotate(-90 74.2 225.8)">VSSA</text>
<text x="76.5" y="225.8" transform="rotate(-90 76.5 225.8)">VSS</text>
<text x="126.3" y="227.2" transform="rotate(-180 126.3 227.2)">G</text>
<text x="126.3" y="224.9" transform="rotate(-180 126.3 224.9)">H</text>
<text x="131.6" y="225.9" transform="rotate(-180 131.6 225.9)">6</text>
<text x="146.9" y="225.9" transform="rotate(-180 146.9 225.9)">20</text>
<text x="154.7" y="227.2" transform="rotate(-180 154.7 227.2)">O15</text>
<text x="154.7" y="224.9" transform="rotate(-180 154.7 224.9)">O16</text>
<text x="41.2" y="231.1" transform="rotate(-90 41.2 231.1)">2</text>
<text x="43.5" y="231.1" transform="rotate(-90 43.5 231.1)">1</text>
<text x="45.8" y="232.2" transform="rotate(-90 45.8 232.2)">22</text>
<text x="48.1" y="232.2" transform="rotate(-90 48.1 232.2)">21</text>
<text x="50.4" y="232.2" transform="rotate(-90 50.4 232.2)">26</text>
<text x="52.7" y="232.2" transform="rotate(-90 52.7 232.2)">25</text>
<text x="55" y="232.2" transform="rotate(-90 55 232.2)">24</text>
<text x="57.2" y="232.2" transform="rotate(-90 57.2 232.2)">23</text>
<text x="59.5" y="232.2" transform="rotate(-90 59.5 232.2)">19</text>
<text x="61.8" y="232.2" transform="rotate(-90 61.8 232.2)">20</text>
<text x="64.1" y="232.2" transform="rotate(-90 64.1 232.2)">32</text>
<text x="66.4" y="232.2" transform="rotate(-90 66.4 232.2)">31</text>
<text x="68.7" y="231.1" transform="rotate(-90 68.7 231.1)">3</text>
<text x="71" y="231.1" transform="rotate(-90 71 231.1)">4</text>
<text x="73.2" y="231.1" transform="rotate(-90 73.2 231.1)">5</text>
<text x="75.5" y="231.1" transform="rotate(-90 75.5 231.1)">6</text>
<text x="126.3" y="231.8" transform="rotate(-180 126.3 231.8)">E</text>
<text x="126.3" y="229.5" transform="rotate(-180 126.3 229.5)">F</text>
<text x="131.6" y="232.8" transform="rotate(-180 131.6 232.8)">7</text>
<text x="131.6" y="230.5" transform="rotate(-180 131.6 230.5)">2</text>
<text x="132.6" y="228.2" transform="rotate(-180 132.6 228.2)">11</text>
<text x="146.9" y="232.8" transform="rotate(-180 146.9 232.8)">17</text>
<text x="146.9" y="230.5" transform="rotate(-180 146.9 230.5)">18</text>
<text x="146.9" y="228.2" transform="rotate(-180 146.9 228.2)">19</text>
<text x="154.7" y="231.8" transform="rotate(-180 154.7 231.8)">O13</text>
<text x="154.7" y="229.5" transform="rotate(-180 154.7 229.5)">O14</text>
<text x="158.8" y="229.6" transform="rotate(-90 158.8 229.6)">SDO</text>
<text x="161.1" y="230.6" transform="rotate(-90 161.1 230.6)">REXT</text>
<text x="112.6" y="239.7" transform="rotate(-180 112.6 239.7)">9</text>
<text x="112.6" y="237.4" transform="rotate(-180 112.6 237.4)">14</text>
<text x="120.5" y="238.6" transform="rotate(-180 120.5 238.6)">CA2</text>
<text x="120.5" y="236.4" transform="rotate(-180 120.5 236.4)">CA3</text>
<text x="126.3" y="238.7" transform="rotate(-180 126.3 238.7)">B</text>
<text x="126.3" y="236.4" transform="rotate(-180 126.3 236.4)">C</text>
<text x="126.3" y="234.1" transform="rotate(-180 126.3 234.1)">D</text>
<text x="131.6" y="235.1" transform="rotate(-180 131.6 235.1)">8</text>
<text x="132.6" y="239.7" transform="rotate(-180 132.6 239.7)">13</text>
<text x="132.6" y="237.4" transform="rotate(-180 132.6 237.4)">10</text>
<text x="146.9" y="239.7" transform="rotate(-180 146.9 239.7)">14</text>
<text x="146.9" y="237.4" transform="rotate(-180 146.9 237.4)">15</text>
<text x="146.9" y="235.1" transform="rotate(-180 146.9 235.1)">16</text>
<text x="154.7" y="238.6" transform="rotate(-180 154.7 238.6)">O10</text>
<text x="154.7" y="236.4" transform="rotate(-180 154.7 236.4)">O11</text>
<text x="154.7" y="234.1" transform="rotate(-180 154.7 234.1)">O12</text>
<text x="112.6" y="241.9" transform="rotate(-180 112.6 241.9)">3</text>
<text x="120.5" y="240.9" transform="rotate(-180 120.5 240.9)">CA1</text>
<text x="126.3" y="240.9" transform="rotate(-180 126.3 240.9)">A</text>
<text x="131.6" y="241.9" transform="rotate(-180 131.6 241.9)">1</text>
<text x="146.9" y="244.2" transform="rotate(-180 146.9 244.2)">12</text>
<text x="146.9" y="241.9" transform="rotate(-180 146.9 241.9)">13</text>
<text x="153.6" y="245.5" transform="rotate(-180 153.6 245.5)">O7</text>
<text x="153.6" y="243.2" transform="rotate(-180 153.6 243.2)">O8</text>
<text x="153.6" y="240.9" transform="rotate(-180 153.6 240.9)">O9</text>
<text x="162.9" y="243.2" transform="rotate(-180 162.9 243.2)">VDD</text>
<text x="162.9" y="240.9" transform="rotate(-180 162.9 240.9)">GND</text>
<text x="168.2" y="241.9" transform="rotate(-180 168.2 241.9)">1</text>
<text x="169.2" y="244.2" transform="rotate(-180 169.2 244.2)">24</text>
<text x="146.9" y="251.1" transform="rotate(-180 146.9 251.1)">9</text>
<text x="146.9" y="248.8" transform="rotate(-180 146.9 248.8)">10</text>
<text x="146.9" y="246.5" transform="rotate(-180 146.9 246.5)">11</text>
<text x="153.6" y="250.1" transform="rotate(-180 153.6 250.1)">O5</text>
<text x="153.6" y="247.8" transform="rotate(-180 153.6 247.8)">O6</text>
<text x="162.9" y="250.1" transform="rotate(-180 162.9 250.1)">OE</text>
<text x="169.2" y="251.1" transform="rotate(-180 169.2 251.1)">21</text>
<text x="112.6" y="255.7" transform="rotate(-180 112.6 255.7)">1</text>
<text x="112.6" y="257.9" transform="rotate(-180 112.6 257.9)">14</text>
<text x="120.5" y="254.6" transform="rotate(-180 120.5 254.6)">CA1</text>
<text x="120.5" y="256.9" transform="rotate(-180 120.5 256.9)">CA3</text>
<text x="126.3" y="256.9" transform="rotate(-180 126.3 256.9)">B</text>
<text x="126.3" y="254.7" transform="rotate(-180 126.3 254.7)">M</text>
<text x="126.3" y="252.4" transform="rotate(-180 126.3 252.4)">P</text>
<text x="131.6" y="255.7" transform="rotate(-180 131.6 255.7)">8</text>
<text x="131.6" y="253.4" transform="rotate(-180 131.6 253.4)">7</text>
<text x="132.6" y="257.9" transform="rotate(-180 132.6 257.9)">10</text>
<text x="146.9" y="257.9" transform="rotate(-180 146.9 257.9)">6</text>
<text x="146.9" y="255.7" transform="rotate(-180 146.9 255.7)">7</text>
<text x="146.9" y="253.4" transform="rotate(-180 146.9 253.4)">8</text>
<text x="153.6" y="256.9" transform="rotate(-180 153.6 256.9)">O2</text>
<text x="153.6" y="254.6" transform="rotate(-180 153.6 254.6)">O3</text>
<text x="153.6" y="252.4" transform="rotate(-180 153.6 252.4)">O4</text>
<text x="162.9" y="252.4" transform="rotate(-180 162.9 252.4)">LE</text>
<text x="168.2" y="253.4" transform="rotate(-180 168.2 253.4)">4</text>
<text x="112.6" y="260.2" transform="rotate(-180 112.6 260.2)">3</text>
<text x="120.5" y="259.2" transform="rotate(-180 120.5 259.2)">CA2</text>
<text x="126.3" y="259.2" transform="rotate(-180 126.3 259.2)">A</text>
<text x="132.6" y="260.2" transform="rotate(-180 132.6 260.2)">11</text>
<text x="146.9" y="260.2" transform="rotate(-180 146.9 260.2)">5</text>
<text x="153.6" y="259.2" transform="rotate(-180 153.6 259.2)">O1</text>
<text x="158.8" y="260.1" transform="rotate(-90 158.8 260.1)">SDI</text>
<text x="161.1" y="260.1" transform="rotate(-90 161.1 260.1)">SCK</text>
<text x="68.7" y="264.7" transform="rotate(-90 68.7 264.7)">4</text>
<text x="71" y="264.7" transform="rotate(-90 71 264.7)">3</text>
<text x="73.2" y="264.7" transform="rotate(-90 73.2 264.7)">2</text>
<text x="75.5" y="264.7" transform="rotate(-90 75.5 264.7)">1</text>
<text x="157.8" y="265.4" transform="rotate(-90 157.8 265.4)">2</text>
<text x="160.1" y="265.4" transform="rotate(-90 160.1 265.4)">3</text>
<text x="53.7" y="270.8" transform="rotate(-90 53.7 270.8)">X1-1</text>
<text x="56" y="270.8" transform="rotate(-90 56 270.8)">X1-2</text>
<text x="58.2" y="270.8" transform="rotate(-90 58.2 270.8)">X1-3</text>
<text x="60.5" y="270.8" transform="rotate(-90 60.5 270.8)">X1-4</text>
</g>
<g font-size="1.6">
<text x="54.9" y="25" transform="rotate(-180 54.9 25)">+</text>
<text x="54.9" y="31.9" transform="rotate(-180 54.9 31.9)">+</text>
<text x="35.3" y="87.3" transform="rotate(-90 35.3 87.3)">Out</text>
<text x="38.7" y="92.7" transform="rotate(-90 38.7 92.7)">VSS</text>
<text x="35.3" y="96.9" transform="rotate(-90 35.3 96.9)">In</text>
<text x="54.9" y="116.4" transform="rotate(-180 54.9 116.4)">+</text>
</g>
</g></defs>
<g fill="none" stroke="#000" stroke-width=".19">
<path d="M50.7 35.9h5M53 31.3h2.3M55.3 24.5h-2.3v27.4h2.3v2.3M57.1 35.9h5M57.6 31.3h4.5M57.6 24.5h4.5M53 47.3h2.3M55.3 58.8v11.4M57.6 42.8h-2.3v2.3h6.8v2.2h-2.3M62.1 42.8h4.6M64.4 42.8v27.4M71.3 42.8h4.5"/>
<path d="M89.6 47.3h-2.3v9.2M128.4 58.8h4.6l11.4 2.3h4.6M158.1 54.2v4.6M162.7 54.2h-2.3v4.6M167.3 54.2h4.5M34.7 72.5v11.4M48.4 62.9v2.7h4.6v4.6M55.3 61.1h-2.3v-2.3h-4.6v2.7M55.3 63.4h6.8M69 65.6h-2.3v4.6M87.3 61.1v4.5h2.3M107.8 72.5h6.9"/>
<path d="M114.7 70.2h-4.6v4.6h4.6M128.4 79.4h20.6M128.4 74.8h4.6l11.4 2.3h4.6M128.4 72.5h4.6l11.4 2.3h4.6M128.4 70.2h4.6l11.4 2.3h4.6M128.4 67.9h4.6l11.4 2.3h4.6M128.4 65.6h4.6l11.4 2.3h4.6M128.4 63.4h4.6l11.4 2.2h4.6M128.4 61.1h4.6l11.4 2.3h4.6M165 79.4h6.8M165 77.1h6.8M34.7 81.6h2.7"/>
<path d="M34.7 99.9h2.7M34.7 97.6v4.6M38.8 81.6h5.1M38.8 99.9h5.1M39.3 90.8h4.6M53 88.5v27.4M57.6 88.5v11.4M64.4 88.5v18.3h7.3M66.7 93h2.7M66.7 88.5v11.4h2.7M70.8 93h5M70.8 99.9h5"/>
<path d="M80.4 99.9h4.6M107.8 93h6.9M114.7 90.8h-4.6v4.5h4.6M128.4 95.3h20.6M128.4 93h20.6M128.4 90.8h20.6M128.4 88.5h20.6M128.4 86.2h20.6M128.4 83.9h20.6M128.4 81.6h20.6M158.1 97.6v16M160.1 87.1h2.8"/>
<path d="M160.4 97.6v4.6h16v171.4M165 88.5h16v185.1M165 86.2h13.7v187.4M34.1 103.3h1.2M34.7 102.8v1.1M49 115.9h1.1M49.6 115.3v1.2M50.7 115.9h4.6M53 109.1h2.7M57.1 109.1h5M57.6 115.9h4.5M73.1 106.8h5"/>
<path d="M128.4 118.2h4.6l11.4 2.3h4.6M128.4 115.9h4.6l11.4 2.3h4.6M128.4 113.6h4.6l11.4 2.3h4.6M139.8 102.2h5.1M146.2 102.2h5.1M162.7 109.1h-2.3v4.5M167.3 109.1h4.5M43.9 129.6h9.1M43.9 136.5h9.1M57.6 129.6h9.1M57.6 136.5h9.1M73.6 129.6h4.5"/>
<path d="M73.6 136.5h4.5M107.8 127.3h6.9M114.7 125.1h-4.6v4.5h4.6M128.4 129.6h4.6l11.4 2.3h4.6M128.4 127.3h4.6l11.4 2.3h4.6M128.4 136.5h20.6M128.4 138.8h20.6M128.4 134.2h20.6M128.4 125.1h4.6l11.4 2.2h4.6M128.4 122.8h4.6l11.4 2.3h4.6M128.4 120.5h4.6l11.4 2.3h4.6M165 134.2h6.8"/>
<path d="M165 131.9h6.8M43.9 143.3h9.1M43.9 150.2h9.1M43.9 157.1h9.1M57.6 143.3h9.1M57.6 150.2h9.1M57.6 157.1h9.1M73.6 143.3h4.5M73.6 150.2h4.5M73.6 157.1h4.5M107.8 147.9h6.9M114.7 145.6h-4.6v4.6h4.6"/>
<path d="M128.4 143.3h20.6M128.4 150.2h20.6M128.4 147.9h20.6M128.4 145.6h20.6M128.4 141.1h20.6M139.8 157.1h5.1M146.2 157.1h5.1M158.1 152.5v16M160.1 141.9h2.8M160.4 152.5v4.6h16M165 143.3h16M165 141.1h13.7"/>
<path d="M59.8 170.8v9.1M75.8 173.1v4.5M80.4 173.1v5.9M83.2 173.1h-9.6v4.5M84.5 173.1h5.1M114.7 179.9h-4.6v4.6h4.6M128.4 179.9h4.6l11.4 2.3h4.6M128.4 177.6h4.6l11.4 2.3h4.6M128.4 175.3h4.6l11.4 2.3h4.6M128.4 173.1h4.6l11.4 2.2h4.6M128.4 170.8h4.6l11.4 2.3h4.6M128.4 168.5h4.6l11.4 2.3h4.6"/>
<path d="M162.7 163.9h-2.3v4.6M167.3 163.9h4.5M41.6 189.1v6.8M43.9 189.1v6.8M46.1 189.1v6.8M48.4 189.1v6.8M50.7 191.3v4.6M53 191.3v4.6M55.3 191.3v4.6M57.6 191.3v4.6M59.8 184.5v11.4M62.1 189.1v6.8"/>
<path d="M64.4 189.1v6.8M66.7 189.1v6.8M69 189.1v6.8M71.3 189.1v6.8M73.6 182.2v13.7M75.8 184.5h7.4M75.8 182.2v13.7M80.4 180.8v3.7M84.5 184.5h5.1M107.8 182.2h6.9M128.4 198.2h20.6M128.4 195.9h20.6"/>
<path d="M128.4 193.6h20.6M128.4 191.3h20.6M128.4 189.1h20.6M128.4 184.5h4.6l11.4 2.3h4.6M128.4 182.2h4.6l11.4 2.3h4.6M160.1 196.8h2.8M165 198.2h16M165 195.9h13.7M165 189.1h6.8M165 186.8h6.8M107.8 202.8h6.9M114.7 200.5h-4.6v4.6h4.6"/>
<path d="M128.4 205.1h20.6M128.4 202.8h20.6M128.4 200.5h20.6M139.8 211.9h5.1M146.2 211.9h5.1M158.1 207.3v16M160.4 207.3v4.6h16M162.7 218.8h-2.3v4.5M167.3 218.8h4.5M41.6 227.9v4.6M43.9 227.9v4.6M46.1 227.9v25.1"/>
<path d="M48.4 227.9v9.1h-9.1v16M50.7 227.9v4.6M53 227.9v6.9h-20.6v18.2M55.3 227.9v25.1M57.6 227.9v18.3M59.8 227.9v4.6M62.1 227.9v4.6M64.4 227.9v29.7h4.6v7.4M66.7 227.9v27.4h4.6v9.7M69 227.9v25.1h4.6v12M71.3 227.9v13.7M73.6 227.9v6.9h6.8"/>
<path d="M75.8 227.9v6.9M107.8 239.3h6.9M114.7 237h-4.6v4.6h4.6M128.4 239.3h20.6M128.4 237h20.6M128.4 234.8h20.6M128.4 232.5h20.6M128.4 230.2h20.6M128.4 227.9h20.6M128.4 225.6h20.6M29.4 248.1h.1M29.5 247.8v.3"/>
<path d="M29.5 249.1v.1M29.6 247.6v.4M29.6 248.9v.2M29.7 247.3l.4 .5-.8 .3zM29.7 247.4v.6M29.7 248.6v.5M29.8 247.4v.5M29.8 248.4v.6M29.8 248.4l-.4 .8M29.8 248.4l.4 .4-.8 .4M29.9 247.5v.4M29.9 248.5v.5"/>
<path d="M30 247.6v.3M30 248.6v.3M30.1 247.8h.1M30.1 248.7v.2M30.2 248.8h.1M30.6 246.9l-1.3 1.2M30.7 247.9l-1.3 1.3M32.4 257.6v2.3h2.3M36.2 248.1h.1M36.3 247.9v.2M36.3 249.2h.1M36.4 247.6v.5"/>
<path d="M36.4 248.9v.2M36.5 247.3l.5 .5-.8 .3zM36.5 247.4v.6M36.5 248.7v.4M36.6 247.4v.5M36.6 248.4v.6M36.6 248.4l.5 .4-.8 .4zM36.7 247.5v.4M36.7 248.5v.5M36.8 247.6v.3M36.8 248.6v.3M36.9 247.8h.1"/>
<path d="M36.9 248.7v.2M37 248.8v.1M37.4 246.9l-1.2 1.2M37.6 247.9l-1.3 1.3M39.3 257.6v2.3h2.3M43.1 248.1h.1M43.2 247.9v.2M43.3 247.6v.5M43.3 248.9v.2M43.4 247.4v.6M43.4 248.7v.4M43.4 247.3l.5 .5-.8 .3z"/>
<path d="M43.5 247.4v.5M43.5 248.4v.6M43.5 248.4l.5 .4-.8 .4zM43.6 247.5v.4M43.6 248.5v.5M43.7 247.6v.3M43.7 248.6v.3M43.8 247.7v.1M43.8 248.7v.2M43.9 248.8v.1M44.3 246.9l-1.2 1.2M44.4 247.9l-1.2 1.3"/>
<path d="M46.1 257.6v2.3h2.3M55.3 257.6v6.9M57.6 250.8v13.7M69 248.5h4.6M69 241.6h5M75.4 241.6h5M80.4 257.6h-4.6v7.4M107.8 257.6h6.9M114.7 255.3h-4.6v4.6h4.6M128.4 259.9h20.6M128.4 257.6h20.6M128.4 255.3h20.6"/>
<path d="M128.4 253h20.6M128.4 241.6h20.6M144.4 250.8h4.6M144.4 248.5h4.6M144.4 246.2h4.6M144.4 243.9h4.6M160.1 251.6h2.8M165 253h16M165 250.8h13.7M165 243.9h6.8M165 241.6h6.8M49 262.2h1.1"/>
<path d="M49.6 261.6v1.2M50.7 262.2h2.3v2.3M62.1 262.2h-2.3v2.3M142.1 273.6h5.1M148.5 273.6h5M158.1 262.2v11.4M160.4 262.2v4.6h16"/>
<circle cx="69" cy="265.9" r=".89"/>
<circle cx="71.3" cy="265.9" r=".89"/>
<circle cx="73.6" cy="265.9" r=".89"/>
<circle cx="75.8" cy="265.9" r=".89"/>
</g>
<g fill="none" stroke="#000" stroke-width=".23">
<path d="M50.6 35.9l1.2-.8v1.6zM55.3 23.1h.8v2.8h-.8zM55.3 30h.8v2.7h-.8zM62.1 22.8v3.4M62.1 29.6v3.5M62.1 34.2v3.4M54.1 54.2v4.6M55.3 54.2a.57 .57 0 0 0-.6 .6 .57 .57 0 0 0 .6 .6 .57 .57 0 0 0-.6 .5 .57 .57 0 0 0 .6 .6 .57 .57 0 0 0-.6 .6 .57 .57 0 0 0 .6 .5 .57 .57 0 0 0-.6 .6 .57 .57 0 0 0 .6 .6M55.3 46.5h4.5v1.7h-4.5zM57.6 42h4.5v1.6h-4.5zM66.7 42h4.6v1.6h-4.6zM75.8 41.1v3.4"/>
<path d="M86.5 56.5h1.6v4.6h-1.6zM89.6 45.6v3.5M90 46.4v1.9M114.7 56.5h13.7v41.1h-13.7zM149 58.8h16v38.8h-16zM162.7 53.4h4.6v1.6h-4.6zM171.8 52.5v3.4M33.6 74.2l1.1-1.7 1.2 1.7M43.9 79.9v3.5M50.7 70.2h18.3v18.3h-18.3zM56.4 63.4l2.3-1.2v2.3zM56.4 62.2v2.3"/>
<path d="M62.1 61.6v3.5M69 63.9v3.5M89.6 63.9v3.5M107.7 72.5l1.3-.8v1.6zM114.7 77.1h13.7M170.1 78.2l1.7 1.2-1.7 1.1M171.8 75.4v3.4M32.4 83.9h6.9v13.7h-6.9zM43.9 89v3.5M43.9 98.2v3.4M75.8 99.1h4.6v1.6h-4.6zM75.8 91.3v3.5"/>
<path d="M85 98.2v3.4M107.7 93l1.3-.7v1.6zM55.3 114.5h.8v2.8h-.8zM62.1 107.3v3.5M62.1 114.2v3.4M78.1 105.1v3.4M114.7 111.3h13.7v41.2h-13.7zM141.5 101l-1.7 1.2 1.7 1.1M149 113.6h16v38.9h-16zM151.3 100.5v3.4M162.7 108.3h4.6v1.6h-4.6zM171.8 107.3v3.5"/>
<path d="M45.6 135.3l-1.7 1.2 1.7 1.1M45.6 128.5l-1.7 1.1 1.7 1.2M53 128.8h4.6v1.6h-4.6zM53 135.7h4.6v1.6h-4.6zM66.7 127.3l6.9 2.3M66.7 134.2l6.9 2.3M69.4 126.9h1.6v.2h-1.6zM69.4 133.8h1.6v.2h-1.6zM70.1 127.1v1.1M70.1 134v1.1M70.4 127.1v1.4M70.4 134v1.3"/>
<path d="M70.4 128.2l-.3 .3M70.4 135.1l-.3 .2M78.1 127.9v3.4M78.1 134.8v3.4M107.7 127.3l1.3-.8v1.6zM114.7 131.9h13.7M170.1 133.1l1.7 1.1-1.7 1.1M171.8 130.2v3.4M45.6 155.9l-1.7 1.2 1.7 1.1M45.6 149.1l-1.7 1.1 1.7 1.1M45.6 142.2l-1.7 1.1 1.7 1.2M53 142.5h4.6v1.6h-4.6z"/>
<path d="M53 149.4h4.6v1.6h-4.6zM53 156.3h4.6v1.6h-4.6zM66.7 141.1l3.4 1.1M66.7 147.9l6.9 2.3M66.7 154.8l6.9 2.3M69.4 140.6h1.6v.2h-1.6zM69.4 147.4h1.6v.3h-1.6zM69.4 154.3h1.6v.2h-1.6zM70.1 140.8v1.2M70.1 147.7v1.1M70.1 154.5v1.2M70.1 142.2l3.5 1.1"/>
<path d="M70.4 140.8v1.4M70.4 147.7v1.4M70.4 154.5v1.4M70.4 142l-.3 .2M70.4 148.8l-.3 .3M70.4 155.7l-.3 .2M78.1 141.6v3.5M78.1 148.5v3.4M78.1 155.3v3.5M107.7 147.9l1.3-.8v1.6zM141.5 155.9l-1.7 1.2 1.7 1.1M151.3 155.3v3.5"/>
<path d="M59.1 179.9h1.5v4.6h-1.5zM72.7 177.6h1.7v4.6h-1.7zM75 177.6h1.6v4.6h-1.6zM78.8 179h3.2M79 179.6h2.8v.7h-2.8zM89.6 171.3v3.5M114.7 166.2h13.7v41.1h-13.7zM149 168.5h16v38.8h-16zM162.7 163.1h4.6v1.6h-4.6zM171.8 162.2v3.4M39.3 195.9h38.8v32h-38.8zM78.8 180.8h3.2"/>
<path d="M89.6 182.8v3.4M107.7 182.2l1.3-.8v1.6zM114.7 186.8h13.7M170.1 187.9l1.7 1.2-1.7 1.1M171.8 185.1v3.4M107.7 202.8l1.3-.8v1.6zM141.5 210.8l-1.7 1.1 1.7 1.2M151.3 210.2v3.4M162.7 218h4.6v1.6h-4.6zM171.8 217.1v3.4M80.4 233v3.5M80.4 239.9v3.4"/>
<path d="M107.7 239.3l1.3-.8v1.6zM114.7 223.3h13.7v20.6h-13.7zM149 223.3h16v38.9h-16zM171.8 239.9v3.4M31.3 246.2h2.3l-1.2 2.3zM31.3 248.5h2.3M31.6 253h1.6v4.6h-1.6zM34.7 258.2v3.4M38.1 246.2h2.3l-1.1 2.3zM38.1 248.5h2.3M38.5 253h1.6v4.6h-1.6zM41.6 258.2v3.4"/>
<path d="M45 246.2h2.3l-1.2 2.3zM45 248.5h2.3M45.3 253h1.6v4.6h-1.6zM48.4 258.2v3.4M54.5 253h1.6v4.6h-1.6zM56.8 246.2h1.6v4.6h-1.6zM71.8 247.3l1.8 1.2-1.8 1.1M80.4 255.9v3.4M107.7 257.6l1.3-.8v1.6zM114.7 250.8h13.7v11.4h-13.7zM170.1 242.8l1.7 1.1-1.7 1.1M62.1 260.5v3.4"/>
<path d="M143.8 272.5l-1.7 1.1 1.7 1.2M153.5 271.9v3.4"/>
<circle cx="34.7" cy="103.4" r="1.14"/>
<circle cx="49.6" cy="115.9" r="1.14"/>
<circle cx="49.6" cy="262.2" r="1.14"/>
</g>
<g fill="#000" stroke="#000" stroke-width=".19">
<path d="M55.7 34.1h.5v3.6h-.5zM56.6 34.1h.5v3.6h-.5zM56.8 29.9h.8v2.9h-.8zM56.8 23h.8v3h-.8zM46.6 61.5h3.6v.5h-3.6zM46.6 62.4h3.6v.5h-3.6zM37.4 79.8h.5v3.7h-.5zM38.4 79.8h.4v3.7h-.4zM69.4 91.2h.5v3.7h-.5zM70.4 91.2h.4v3.7h-.4zM37.4 98.1h.5v3.6h-.5zM38.4 98.1h.4v3.6h-.4z"/>
<path d="M55.7 107.2h.5v3.7h-.5zM56.6 107.2h.5v3.7h-.5zM56.8 114.4h.8v3h-.8zM69.4 98.1h.5v3.6h-.5zM70.4 98.1h.4v3.6h-.4zM71.7 104.9h.5v3.7h-.5zM72.6 104.9h.5v3.7h-.5zM144.9 100.4h.4v3.6h-.4zM145.8 100.4h.4v3.6h-.4zM144.9 155.2h.4v3.7h-.4zM145.8 155.2h.4v3.7h-.4zM83.1 171.2h.5v3.7h-.5z"/>
<path d="M84.1 171.2h.4v3.7h-.4zM83.1 182.7h.5v3.6h-.5zM84.1 182.7h.4v3.6h-.4zM144.9 210.1h.4v3.6h-.4zM145.8 210.1h.4v3.6h-.4zM74 239.8h.5v3.6h-.5zM74.9 239.8h.5v3.6h-.5zM147.2 271.8h.4v3.6h-.4zM148.1 271.8h.4v3.6h-.4z"/>
</g>
<g fill="none" stroke="#000" stroke-width=".55">
<path d="M53 264.5v1.1M55.3 264.5v1.1M57.6 264.5v1.1M59.8 264.5v1.1"/>
<circle cx="66.7" cy="129.6" r=".11"/>
<circle cx="66.7" cy="134.2" r=".11"/>
<circle cx="66.7" cy="127.4" r=".11"/>
<circle cx="66.7" cy="136.5" r=".11"/>
<circle cx="66.7" cy="147.9" r=".11"/>
<circle cx="66.7" cy="157.1" r=".11"/>
<circle cx="66.7" cy="143.4" r=".11"/>
<circle cx="66.7" cy="150.2" r=".11"/>
<circle cx="66.7" cy="154.8" r=".11"/>
<circle cx="66.7" cy="141.1" r=".11"/>
</g>
<path d="M66.7 261h11.4v6.9h-11.4z" fill="none" stroke="#000" stroke-width=".38"/>
<g fill="#000" stroke="#000" stroke-width=".19">
<circle cx="53" cy="31.4" r=".47"/>
<circle cx="53" cy="35.9" r=".47"/>
<circle cx="53" cy="47.4" r=".47"/>
<circle cx="64.4" cy="42.8" r=".47"/>
<circle cx="55.3" cy="63.4" r=".47"/>
<circle cx="55.3" cy="61.1" r=".47"/>
<circle cx="110.1" cy="72.5" r=".47"/>
<circle cx="34.7" cy="99.9" r=".47"/>
<circle cx="34.7" cy="81.7" r=".47"/>
<circle cx="66.7" cy="93.1" r=".47"/>
<circle cx="110.1" cy="93.1" r=".47"/>
<circle cx="53" cy="115.9" r=".47"/>
<circle cx="53" cy="109.1" r=".47"/>
<circle cx="110.1" cy="127.4" r=".47"/>
<circle cx="110.1" cy="147.9" r=".47"/>
<circle cx="176.4" cy="157.1" r=".47"/>
<circle cx="178.7" cy="141.1" r=".47"/>
<circle cx="181" cy="143.4" r=".47"/>
<circle cx="75.8" cy="173.1" r=".47"/>
<circle cx="80.4" cy="173.1" r=".47"/>
<circle cx="75.8" cy="184.5" r=".47"/>
<circle cx="80.4" cy="184.5" r=".47"/>
<circle cx="110.1" cy="182.2" r=".47"/>
<circle cx="178.7" cy="195.9" r=".47"/>
<circle cx="181" cy="198.2" r=".47"/>
<circle cx="110.1" cy="202.8" r=".47"/>
<circle cx="176.4" cy="211.9" r=".47"/>
<circle cx="75.8" cy="234.8" r=".47"/>
<circle cx="110.1" cy="239.4" r=".47"/>
<circle cx="69" cy="241.6" r=".47"/>
<circle cx="69" cy="248.5" r=".47"/>
<circle cx="71.3" cy="241.6" r=".47"/>
<circle cx="110.1" cy="257.6" r=".47"/>
<circle cx="178.7" cy="250.8" r=".47"/>
<circle cx="181" cy="253.1" r=".47"/>
<circle cx="176.4" cy="266.8" r=".47"/>
</g>
<use href="#words"/>
</svg>
